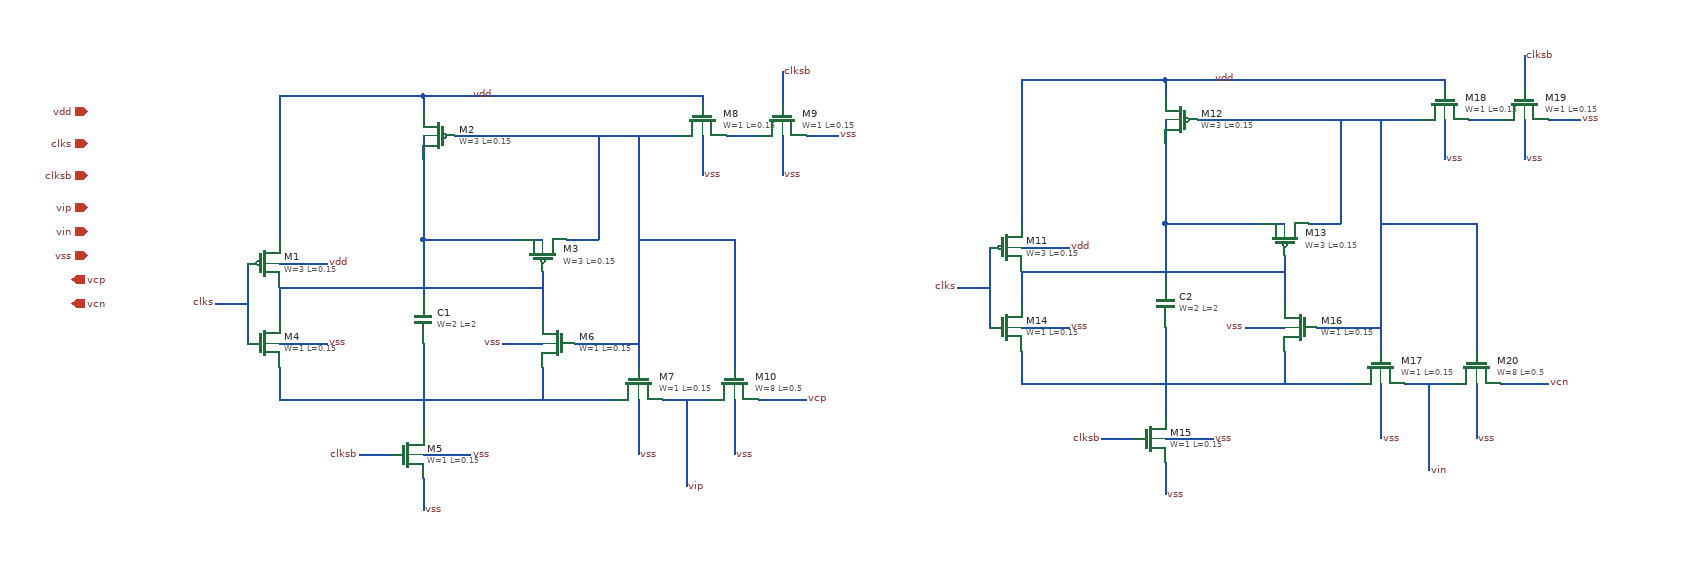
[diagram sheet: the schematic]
v {xschem version=3.4.6RC file_version=1.2
}
G {}
K {}
V {}
S {}
E {}
N 900 -620 900 -580 {
lab=#net1}
N 1080 -810 1080 -780 {
lab=#net2}
N 1200 -680 1230 -680 {
lab=#net2}
N 1230 -640 1230 -580 {
lab=#net1}
N 900 -780 900 -680 {
lab=vdd}
N 1120 -810 1400 -810 {
lab=#net3}
N 1460 -810 1500 -810 {
lab=#net4}
N 1260 -680 1300 -680 {
lab=#net3}
N 1300 -810 1300 -680 {
lab=#net3}
N 1350 -810 1350 -520 {
lab=#net3}
N 1270 -550 1350 -550 {
lab=#net3}
N 1350 -680 1440 -680 {
lab=#net3}
N 900 -520 900 -480 {
lab=#net5}
N 900 -480 1320 -480 {
lab=#net5}
N 1230 -520 1230 -480 {
lab=#net5}
N 1080 -680 1200 -680 {
lab=#net2}
N 1080 -780 1080 -680 {
lab=#net2}
N 900 -620 1230 -620 {
lab=#net1}
N 860 -650 860 -550 {
lab=clks}
N 1080 -480 1080 -440 {
lab=#net5}
N 1000 -410 1040 -410 {
lab=clksb}
N 820 -600 860 -600 {
lab=clks}
N 1080 -860 1080 -840 {
lab=vdd}
N 1080 -860 1430 -860 {
lab=vdd}
N 1430 -860 1430 -850 {
lab=vdd}
N 900 -860 900 -780 {
lab=vdd}
N 900 -860 1080 -860 {
lab=vdd}
N 1080 -680 1080 -610 {
lab=#net2}
N 1080 -550 1080 -480 {
lab=#net5}
N 1080 -380 1080 -340 {
lab=vss}
N 1380 -480 1440 -480 {
lab=vip}
N 1440 -680 1470 -680 {
lab=#net3}
N 1470 -680 1470 -520 {
lab=#net3}
N 1500 -480 1560 -480 {
lab=vcp}
N 1410 -480 1410 -370 {
lab=vip}
N 1350 -480 1350 -410 {
lab=vss}
N 1470 -480 1470 -410 {
lab=vss}
N 1180 -550 1230 -550 {
lab=vss}
N 900 -550 960 -550 {
lab=vss}
N 900 -650 960 -650 {
lab=vdd}
N 1430 -810 1430 -760 {
lab=vss}
N 1530 -810 1530 -760 {
lab=vss}
N 1080 -410 1140 -410 {
lab=vss}
N 1530 -890 1530 -850 {
lab=clksb}
N 1560 -810 1600 -810 {
lab=vss}
N 1830 -640 1830 -600 {
lab=#net6}
N 2010 -830 2010 -800 {
lab=#net7}
N 2130 -700 2160 -700 {
lab=#net7}
N 2160 -660 2160 -600 {
lab=#net6}
N 1830 -800 1830 -700 {
lab=vdd}
N 2050 -830 2330 -830 {
lab=#net8}
N 2390 -830 2430 -830 {
lab=#net9}
N 2190 -700 2230 -700 {
lab=#net8}
N 2230 -830 2230 -700 {
lab=#net8}
N 2280 -830 2280 -540 {
lab=#net8}
N 2200 -570 2280 -570 {
lab=#net8}
N 2280 -700 2370 -700 {
lab=#net8}
N 1830 -540 1830 -500 {
lab=#net10}
N 1830 -500 2250 -500 {
lab=#net10}
N 2160 -540 2160 -500 {
lab=#net10}
N 2010 -700 2130 -700 {
lab=#net7}
N 2010 -800 2010 -700 {
lab=#net7}
N 1830 -640 2160 -640 {
lab=#net6}
N 1790 -670 1790 -570 {
lab=clks}
N 2010 -500 2010 -460 {
lab=#net10}
N 1930 -430 1970 -430 {
lab=clksb}
N 1750 -620 1790 -620 {
lab=clks}
N 2010 -880 2010 -860 {
lab=vdd}
N 2010 -880 2360 -880 {
lab=vdd}
N 2360 -880 2360 -870 {
lab=vdd}
N 1830 -880 1830 -800 {
lab=vdd}
N 1830 -880 2010 -880 {
lab=vdd}
N 2010 -700 2010 -630 {
lab=#net7}
N 2010 -570 2010 -500 {
lab=#net10}
N 2010 -400 2010 -360 {
lab=vss}
N 2310 -500 2370 -500 {
lab=vin}
N 2370 -700 2400 -700 {
lab=#net8}
N 2400 -700 2400 -540 {
lab=#net8}
N 2430 -500 2490 -500 {
lab=vcn}
N 2340 -500 2340 -390 {
lab=vin}
N 2280 -500 2280 -430 {
lab=vss}
N 2400 -500 2400 -430 {
lab=vss}
N 2110 -570 2160 -570 {
lab=vss}
N 1830 -570 1890 -570 {
lab=vss}
N 1830 -670 1890 -670 {
lab=vdd}
N 2360 -830 2360 -780 {
lab=vss}
N 2460 -830 2460 -780 {
lab=vss}
N 2010 -430 2070 -430 {
lab=vss}
N 2460 -910 2460 -870 {
lab=clkb}
N 2490 -830 2530 -830 {
lab=vss}
C {sky130_fd_pr/pfet_01v8.sym} 880 -650 0 0 {name=M1
L=0.15
W=3
nf=1
mult=1
ad="'int((nf+1)/2) * W/nf * 0.29'" 
pd="'2*int((nf+1)/2) * (W/nf + 0.29)'"
as="'int((nf+2)/2) * W/nf * 0.29'" 
ps="'2*int((nf+2)/2) * (W/nf + 0.29)'"
nrd="'0.29 / W'" nrs="'0.29 / W'"
sa=0 sb=0 sd=0
model=pfet_01v8
spiceprefix=X
}
C {sky130_fd_pr/pfet_01v8.sym} 1100 -810 0 1 {name=M2
L=0.15
W=3
nf=1
mult=1
ad="'int((nf+1)/2) * W/nf * 0.29'" 
pd="'2*int((nf+1)/2) * (W/nf + 0.29)'"
as="'int((nf+2)/2) * W/nf * 0.29'" 
ps="'2*int((nf+2)/2) * (W/nf + 0.29)'"
nrd="'0.29 / W'" nrs="'0.29 / W'"
sa=0 sb=0 sd=0
model=pfet_01v8
spiceprefix=X
}
C {sky130_fd_pr/pfet_01v8.sym} 1230 -660 3 0 {name=M3
L=0.15
W=3
nf=1
mult=1
ad="'int((nf+1)/2) * W/nf * 0.29'" 
pd="'2*int((nf+1)/2) * (W/nf + 0.29)'"
as="'int((nf+2)/2) * W/nf * 0.29'" 
ps="'2*int((nf+2)/2) * (W/nf + 0.29)'"
nrd="'0.29 / W'" nrs="'0.29 / W'"
sa=0 sb=0 sd=0
model=pfet_01v8
spiceprefix=X
}
C {sky130_fd_pr/nfet_01v8.sym} 880 -550 0 0 {name=M4
L=0.15
W=1
nf=1 
mult=1
ad="'int((nf+1)/2) * W/nf * 0.29'" 
pd="'2*int((nf+1)/2) * (W/nf + 0.29)'"
as="'int((nf+2)/2) * W/nf * 0.29'" 
ps="'2*int((nf+2)/2) * (W/nf + 0.29)'"
nrd="'0.29 / W'" nrs="'0.29 / W'"
sa=0 sb=0 sd=0
model=nfet_01v8
spiceprefix=X
}
C {sky130_fd_pr/nfet_01v8.sym} 1060 -410 0 0 {name=M5
L=0.15
W=1
nf=1 
mult=1
ad="'int((nf+1)/2) * W/nf * 0.29'" 
pd="'2*int((nf+1)/2) * (W/nf + 0.29)'"
as="'int((nf+2)/2) * W/nf * 0.29'" 
ps="'2*int((nf+2)/2) * (W/nf + 0.29)'"
nrd="'0.29 / W'" nrs="'0.29 / W'"
sa=0 sb=0 sd=0
model=nfet_01v8
spiceprefix=X
}
C {sky130_fd_pr/nfet_01v8.sym} 1250 -550 0 1 {name=M6
L=0.15
W=1
nf=1 
mult=1
ad="'int((nf+1)/2) * W/nf * 0.29'" 
pd="'2*int((nf+1)/2) * (W/nf + 0.29)'"
as="'int((nf+2)/2) * W/nf * 0.29'" 
ps="'2*int((nf+2)/2) * (W/nf + 0.29)'"
nrd="'0.29 / W'" nrs="'0.29 / W'"
sa=0 sb=0 sd=0
model=nfet_01v8
spiceprefix=X
}
C {sky130_fd_pr/nfet_01v8.sym} 1350 -500 3 1 {name=M7
L=0.15
W=1
nf=1 
mult=1
ad="'int((nf+1)/2) * W/nf * 0.29'" 
pd="'2*int((nf+1)/2) * (W/nf + 0.29)'"
as="'int((nf+2)/2) * W/nf * 0.29'" 
ps="'2*int((nf+2)/2) * (W/nf + 0.29)'"
nrd="'0.29 / W'" nrs="'0.29 / W'"
sa=0 sb=0 sd=0
model=nfet_01v8
spiceprefix=X
}
C {sky130_fd_pr/nfet_01v8.sym} 1430 -830 3 1 {name=M8
L=0.15
W=1
nf=1 
mult=1
ad="'int((nf+1)/2) * W/nf * 0.29'" 
pd="'2*int((nf+1)/2) * (W/nf + 0.29)'"
as="'int((nf+2)/2) * W/nf * 0.29'" 
ps="'2*int((nf+2)/2) * (W/nf + 0.29)'"
nrd="'0.29 / W'" nrs="'0.29 / W'"
sa=0 sb=0 sd=0
model=nfet_01v8
spiceprefix=X
}
C {sky130_fd_pr/nfet_01v8.sym} 1530 -830 3 1 {name=M9
L=0.15
W=1
nf=1 
mult=1
ad="'int((nf+1)/2) * W/nf * 0.29'" 
pd="'2*int((nf+1)/2) * (W/nf + 0.29)'"
as="'int((nf+2)/2) * W/nf * 0.29'" 
ps="'2*int((nf+2)/2) * (W/nf + 0.29)'"
nrd="'0.29 / W'" nrs="'0.29 / W'"
sa=0 sb=0 sd=0
model=nfet_01v8
spiceprefix=X
}
C {sky130_fd_pr/cap_mim_m3_1.sym} 1080 -580 0 0 {name=C1 model=cap_mim_m3_1 W=2 L=2 MF=4 spiceprefix=X}
C {sky130_fd_pr/nfet_01v8.sym} 1470 -500 1 0 {name=M10
L=0.5
W=8
nf=1 
mult=1
ad="'int((nf+1)/2) * W/nf * 0.29'" 
pd="'2*int((nf+1)/2) * (W/nf + 0.29)'"
as="'int((nf+2)/2) * W/nf * 0.29'" 
ps="'2*int((nf+2)/2) * (W/nf + 0.29)'"
nrd="'0.29 / W'" nrs="'0.29 / W'"
sa=0 sb=0 sd=0
model=nfet_01v8
spiceprefix=X
}
C {devices/lab_wire.sym} 960 -650 0 1 {name=p1 sig_type=std_logic lab=vdd}
C {devices/lab_wire.sym} 960 -550 0 1 {name=p2 sig_type=std_logic lab=vss}
C {devices/lab_wire.sym} 1140 -410 0 1 {name=p3 sig_type=std_logic lab=vss}
C {devices/lab_wire.sym} 1180 -550 0 0 {name=p4 sig_type=std_logic lab=vss}
C {devices/lab_wire.sym} 1350 -410 2 0 {name=p5 sig_type=std_logic lab=vss}
C {devices/lab_wire.sym} 1470 -410 2 0 {name=p6 sig_type=std_logic lab=vss}
C {devices/lab_wire.sym} 1430 -760 2 0 {name=p7 sig_type=std_logic lab=vss}
C {devices/lab_wire.sym} 1530 -760 2 0 {name=p8 sig_type=std_logic lab=vss}
C {devices/lab_wire.sym} 1600 -810 2 0 {name=p9 sig_type=std_logic lab=vss}
C {devices/lab_wire.sym} 1530 -890 0 1 {name=p10 sig_type=std_logic lab=clksb}
C {devices/lab_wire.sym} 820 -600 0 0 {name=p11 sig_type=std_logic lab=clks}
C {devices/lab_wire.sym} 1000 -410 0 0 {name=p12 sig_type=std_logic lab=clksb}
C {devices/lab_wire.sym} 1080 -340 0 1 {name=p13 sig_type=std_logic lab=vss}
C {devices/lab_wire.sym} 1410 -370 2 0 {name=p14 sig_type=std_logic lab=vip}
C {devices/lab_wire.sym} 1560 -480 2 0 {name=p15 sig_type=std_logic lab=vcp}
C {devices/lab_wire.sym} 1140 -860 0 1 {name=p16 sig_type=std_logic lab=vdd}
C {devices/ipin.sym} 660 -840 0 0 {name=p17 lab=vdd}
C {devices/ipin.sym} 660 -800 0 0 {name=p18 lab=clks}
C {devices/ipin.sym} 660 -760 0 0 {name=p19 lab=clksb}
C {devices/ipin.sym} 660 -720 0 0 {name=p20 lab=vip}
C {sky130_fd_pr/pfet_01v8.sym} 1810 -670 0 0 {name=M11
L=0.15
W=3
nf=1
mult=1
ad="'int((nf+1)/2) * W/nf * 0.29'" 
pd="'2*int((nf+1)/2) * (W/nf + 0.29)'"
as="'int((nf+2)/2) * W/nf * 0.29'" 
ps="'2*int((nf+2)/2) * (W/nf + 0.29)'"
nrd="'0.29 / W'" nrs="'0.29 / W'"
sa=0 sb=0 sd=0
model=pfet_01v8
spiceprefix=X
}
C {sky130_fd_pr/pfet_01v8.sym} 2030 -830 0 1 {name=M12
L=0.15
W=3
nf=1
mult=1
ad="'int((nf+1)/2) * W/nf * 0.29'" 
pd="'2*int((nf+1)/2) * (W/nf + 0.29)'"
as="'int((nf+2)/2) * W/nf * 0.29'" 
ps="'2*int((nf+2)/2) * (W/nf + 0.29)'"
nrd="'0.29 / W'" nrs="'0.29 / W'"
sa=0 sb=0 sd=0
model=pfet_01v8
spiceprefix=X
}
C {sky130_fd_pr/pfet_01v8.sym} 2160 -680 3 0 {name=M13
L=0.15
W=3
nf=1
mult=1
ad="'int((nf+1)/2) * W/nf * 0.29'" 
pd="'2*int((nf+1)/2) * (W/nf + 0.29)'"
as="'int((nf+2)/2) * W/nf * 0.29'" 
ps="'2*int((nf+2)/2) * (W/nf + 0.29)'"
nrd="'0.29 / W'" nrs="'0.29 / W'"
sa=0 sb=0 sd=0
model=pfet_01v8
spiceprefix=X
}
C {sky130_fd_pr/nfet_01v8.sym} 1810 -570 0 0 {name=M14
L=0.15
W=1
nf=1 
mult=1
ad="'int((nf+1)/2) * W/nf * 0.29'" 
pd="'2*int((nf+1)/2) * (W/nf + 0.29)'"
as="'int((nf+2)/2) * W/nf * 0.29'" 
ps="'2*int((nf+2)/2) * (W/nf + 0.29)'"
nrd="'0.29 / W'" nrs="'0.29 / W'"
sa=0 sb=0 sd=0
model=nfet_01v8
spiceprefix=X
}
C {sky130_fd_pr/nfet_01v8.sym} 1990 -430 0 0 {name=M15
L=0.15
W=1
nf=1 
mult=1
ad="'int((nf+1)/2) * W/nf * 0.29'" 
pd="'2*int((nf+1)/2) * (W/nf + 0.29)'"
as="'int((nf+2)/2) * W/nf * 0.29'" 
ps="'2*int((nf+2)/2) * (W/nf + 0.29)'"
nrd="'0.29 / W'" nrs="'0.29 / W'"
sa=0 sb=0 sd=0
model=nfet_01v8
spiceprefix=X
}
C {sky130_fd_pr/nfet_01v8.sym} 2180 -570 0 1 {name=M16
L=0.15
W=1
nf=1 
mult=1
ad="'int((nf+1)/2) * W/nf * 0.29'" 
pd="'2*int((nf+1)/2) * (W/nf + 0.29)'"
as="'int((nf+2)/2) * W/nf * 0.29'" 
ps="'2*int((nf+2)/2) * (W/nf + 0.29)'"
nrd="'0.29 / W'" nrs="'0.29 / W'"
sa=0 sb=0 sd=0
model=nfet_01v8
spiceprefix=X
}
C {sky130_fd_pr/nfet_01v8.sym} 2280 -520 3 1 {name=M17
L=0.15
W=1
nf=1 
mult=1
ad="'int((nf+1)/2) * W/nf * 0.29'" 
pd="'2*int((nf+1)/2) * (W/nf + 0.29)'"
as="'int((nf+2)/2) * W/nf * 0.29'" 
ps="'2*int((nf+2)/2) * (W/nf + 0.29)'"
nrd="'0.29 / W'" nrs="'0.29 / W'"
sa=0 sb=0 sd=0
model=nfet_01v8
spiceprefix=X
}
C {sky130_fd_pr/nfet_01v8.sym} 2360 -850 3 1 {name=M18
L=0.15
W=1
nf=1 
mult=1
ad="'int((nf+1)/2) * W/nf * 0.29'" 
pd="'2*int((nf+1)/2) * (W/nf + 0.29)'"
as="'int((nf+2)/2) * W/nf * 0.29'" 
ps="'2*int((nf+2)/2) * (W/nf + 0.29)'"
nrd="'0.29 / W'" nrs="'0.29 / W'"
sa=0 sb=0 sd=0
model=nfet_01v8
spiceprefix=X
}
C {sky130_fd_pr/nfet_01v8.sym} 2460 -850 3 1 {name=M19
L=0.15
W=1
nf=1 
mult=1
ad="'int((nf+1)/2) * W/nf * 0.29'" 
pd="'2*int((nf+1)/2) * (W/nf + 0.29)'"
as="'int((nf+2)/2) * W/nf * 0.29'" 
ps="'2*int((nf+2)/2) * (W/nf + 0.29)'"
nrd="'0.29 / W'" nrs="'0.29 / W'"
sa=0 sb=0 sd=0
model=nfet_01v8
spiceprefix=X
}
C {sky130_fd_pr/cap_mim_m3_1.sym} 2010 -600 0 0 {name=C2 model=cap_mim_m3_1 W=2 L=2 MF=4 spiceprefix=X}
C {sky130_fd_pr/nfet_01v8.sym} 2400 -520 1 0 {name=M20
L=0.5
W=8
nf=1 
mult=1
ad="'int((nf+1)/2) * W/nf * 0.29'" 
pd="'2*int((nf+1)/2) * (W/nf + 0.29)'"
as="'int((nf+2)/2) * W/nf * 0.29'" 
ps="'2*int((nf+2)/2) * (W/nf + 0.29)'"
nrd="'0.29 / W'" nrs="'0.29 / W'"
sa=0 sb=0 sd=0
model=nfet_01v8
spiceprefix=X
}
C {devices/lab_wire.sym} 1890 -670 0 1 {name=p23 sig_type=std_logic lab=vdd}
C {devices/lab_wire.sym} 1890 -570 0 1 {name=p24 sig_type=std_logic lab=vss}
C {devices/lab_wire.sym} 2070 -430 0 1 {name=p25 sig_type=std_logic lab=vss}
C {devices/lab_wire.sym} 2110 -570 0 0 {name=p26 sig_type=std_logic lab=vss}
C {devices/lab_wire.sym} 2280 -430 2 0 {name=p27 sig_type=std_logic lab=vss}
C {devices/lab_wire.sym} 2400 -430 2 0 {name=p28 sig_type=std_logic lab=vss}
C {devices/lab_wire.sym} 2360 -780 2 0 {name=p29 sig_type=std_logic lab=vss}
C {devices/lab_wire.sym} 2460 -780 2 0 {name=p30 sig_type=std_logic lab=vss}
C {devices/lab_wire.sym} 2530 -830 2 0 {name=p31 sig_type=std_logic lab=vss}
C {devices/lab_wire.sym} 2460 -910 0 1 {name=p32 sig_type=std_logic lab=clksb}
C {devices/lab_wire.sym} 1750 -620 0 0 {name=p33 sig_type=std_logic lab=clks}
C {devices/lab_wire.sym} 1930 -430 0 0 {name=p34 sig_type=std_logic lab=clksb}
C {devices/lab_wire.sym} 2010 -360 0 1 {name=p35 sig_type=std_logic lab=vss}
C {devices/lab_wire.sym} 2340 -390 2 0 {name=p36 sig_type=std_logic lab=vin}
C {devices/lab_wire.sym} 2490 -500 2 0 {name=p37 sig_type=std_logic lab=vcn}
C {devices/lab_wire.sym} 2070 -880 0 1 {name=p38 sig_type=std_logic lab=vdd}
C {devices/ipin.sym} 660 -690 0 0 {name=p21 lab=vin}
C {devices/ipin.sym} 660 -660 0 0 {name=p22 lab=vss}
C {devices/opin.sym} 640 -630 0 0 {name=p39 lab=vcp}
C {devices/opin.sym} 640 -600 0 0 {name=p40 lab=vcn}
